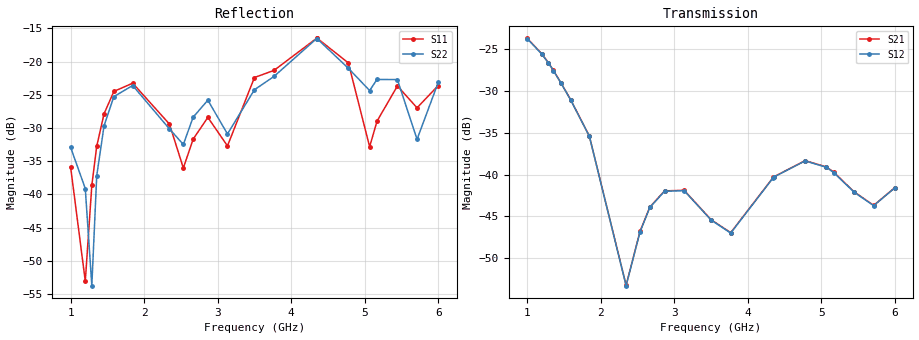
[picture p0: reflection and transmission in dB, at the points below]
!Agilent Technologies,E8364B,MY43040528,A.07.50.67
!Agilent E8364B: A.07.50.67
!Date: Sunday, March 01, 2026 16:29:32
!Correction: S11(Full 2 Port(1,2))
!S21(Full 2 Port(1,2))
!S12(Full 2 Port(1,2))
!S22(Full 2 Port(1,2))
!S2P File: Measurements: S11, S21, S12, S22:
# Hz S  dB  R 50
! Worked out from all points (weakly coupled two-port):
!   451 points, 1 GHz to 6 GHz, reference 50 ohm
!   highest |S21| = -23.74 dB at 1 GHz (marker M1); lowest = -53.2 dB at 2.344 GHz (marker M2)
!   lowest |S11| = -53.1 dB at 1.2 GHz (marker M3), VSWR 1.00, Z = 50.1 - j0.164 ohm
!   |S11| at or under -10 dB: start of sweep to end of sweep
!   |S22| runs from -53.8 to -16.5 dB; largest |S21 - S12| = 0.00031
!   S11 on the Smith chart (normalised r, x): 1 GHz: 1.03, +0.01; 4.356 GHz: 1.20, -0.26; 6 GHz: 0.97, -0.13
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1e9  -35.83 22.0  -23.74 153.1  -23.78 153.1  -32.89 -2.1
1.2e9  -53.07 -47.5  -25.60 38.7  -25.64 38.7  -39.11 -6.2
1.288889e9  -38.63 -145.8  -26.66 -11.8  -26.70 -11.7  -53.74 75.1
1.355556e9  -32.74 -163.9  -27.56 -49.1  -27.59 -49.0  -37.19 113.6
1.455556e9  -27.84 168.8  -29.01 -104.2  -29.04 -104.1  -29.64 91.1
1.588889e9  -24.48 137.7  -31.04 -176.1  -31.07 -176.1  -25.26 56.7
1.844444e9  -23.24 87.0  -35.40 47.5  -35.43 47.6  -23.59 -3.7
2.344444e9  -29.40 25.6  -53.22 -150.6  -53.27 -150.6  -30.13 -75.4
2.533333e9  -36.02 48.5  -46.79 169.1  -46.85 169.2  -32.47 -52.8
2.666667e9  -31.67 75.6  -43.89 104.3  -43.93 104.4  -28.36 -54.5
2.866667e9  -28.39 51.9  -41.95 0.1  -42.00 -0.0  -25.80 -93.3
3.133333e9  -32.69 64.1  -41.88 -141.8  -41.92 -141.7  -30.89 -126.7
3.5e9  -22.39 50.4  -45.39 37.1  -45.43 37.2  -24.23 -127.9
3.766667e9  -21.31 25.6  -46.94 -66.0  -46.99 -65.9  -22.22 -156.3
4.344444e9  -16.49 -43.7  -40.34 22.4  -40.38 22.4  -16.54 111.2
4.355556e9  -16.49 -45.4  -40.26 16.5  -40.29 16.4  -16.57 109.0
4.777778e9  -20.20 -114.9  -38.34 139.9  -38.37 140.0  -21.00 36.8
5.066667e9  -32.82 -105.9  -39.08 -30.3  -39.13 -30.2  -24.35 39.5
5.166667e9  -28.96 -68.8  -39.71 -90.6  -39.76 -90.6  -22.68 32.9
5.444444e9  -23.66 -100.3  -42.06 93.3  -42.11 93.3  -22.70 -20.0
5.711111e9  -26.95 -107.0  -43.68 -95.7  -43.71 -95.7  -31.70 -17.7
6e9  -23.59 -100.7  -41.55 59.8  -41.58 59.7  -23.11 -16.8
